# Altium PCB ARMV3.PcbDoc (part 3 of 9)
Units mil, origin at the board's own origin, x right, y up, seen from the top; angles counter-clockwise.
Board outline 4700.79 x 3937.01 mil, 6 copper layers (Top Layer, GND02, ART03, ART04, PWR05, Bottom Layer); 703 components, 513 nets, 2343 pads, 1252 vias.

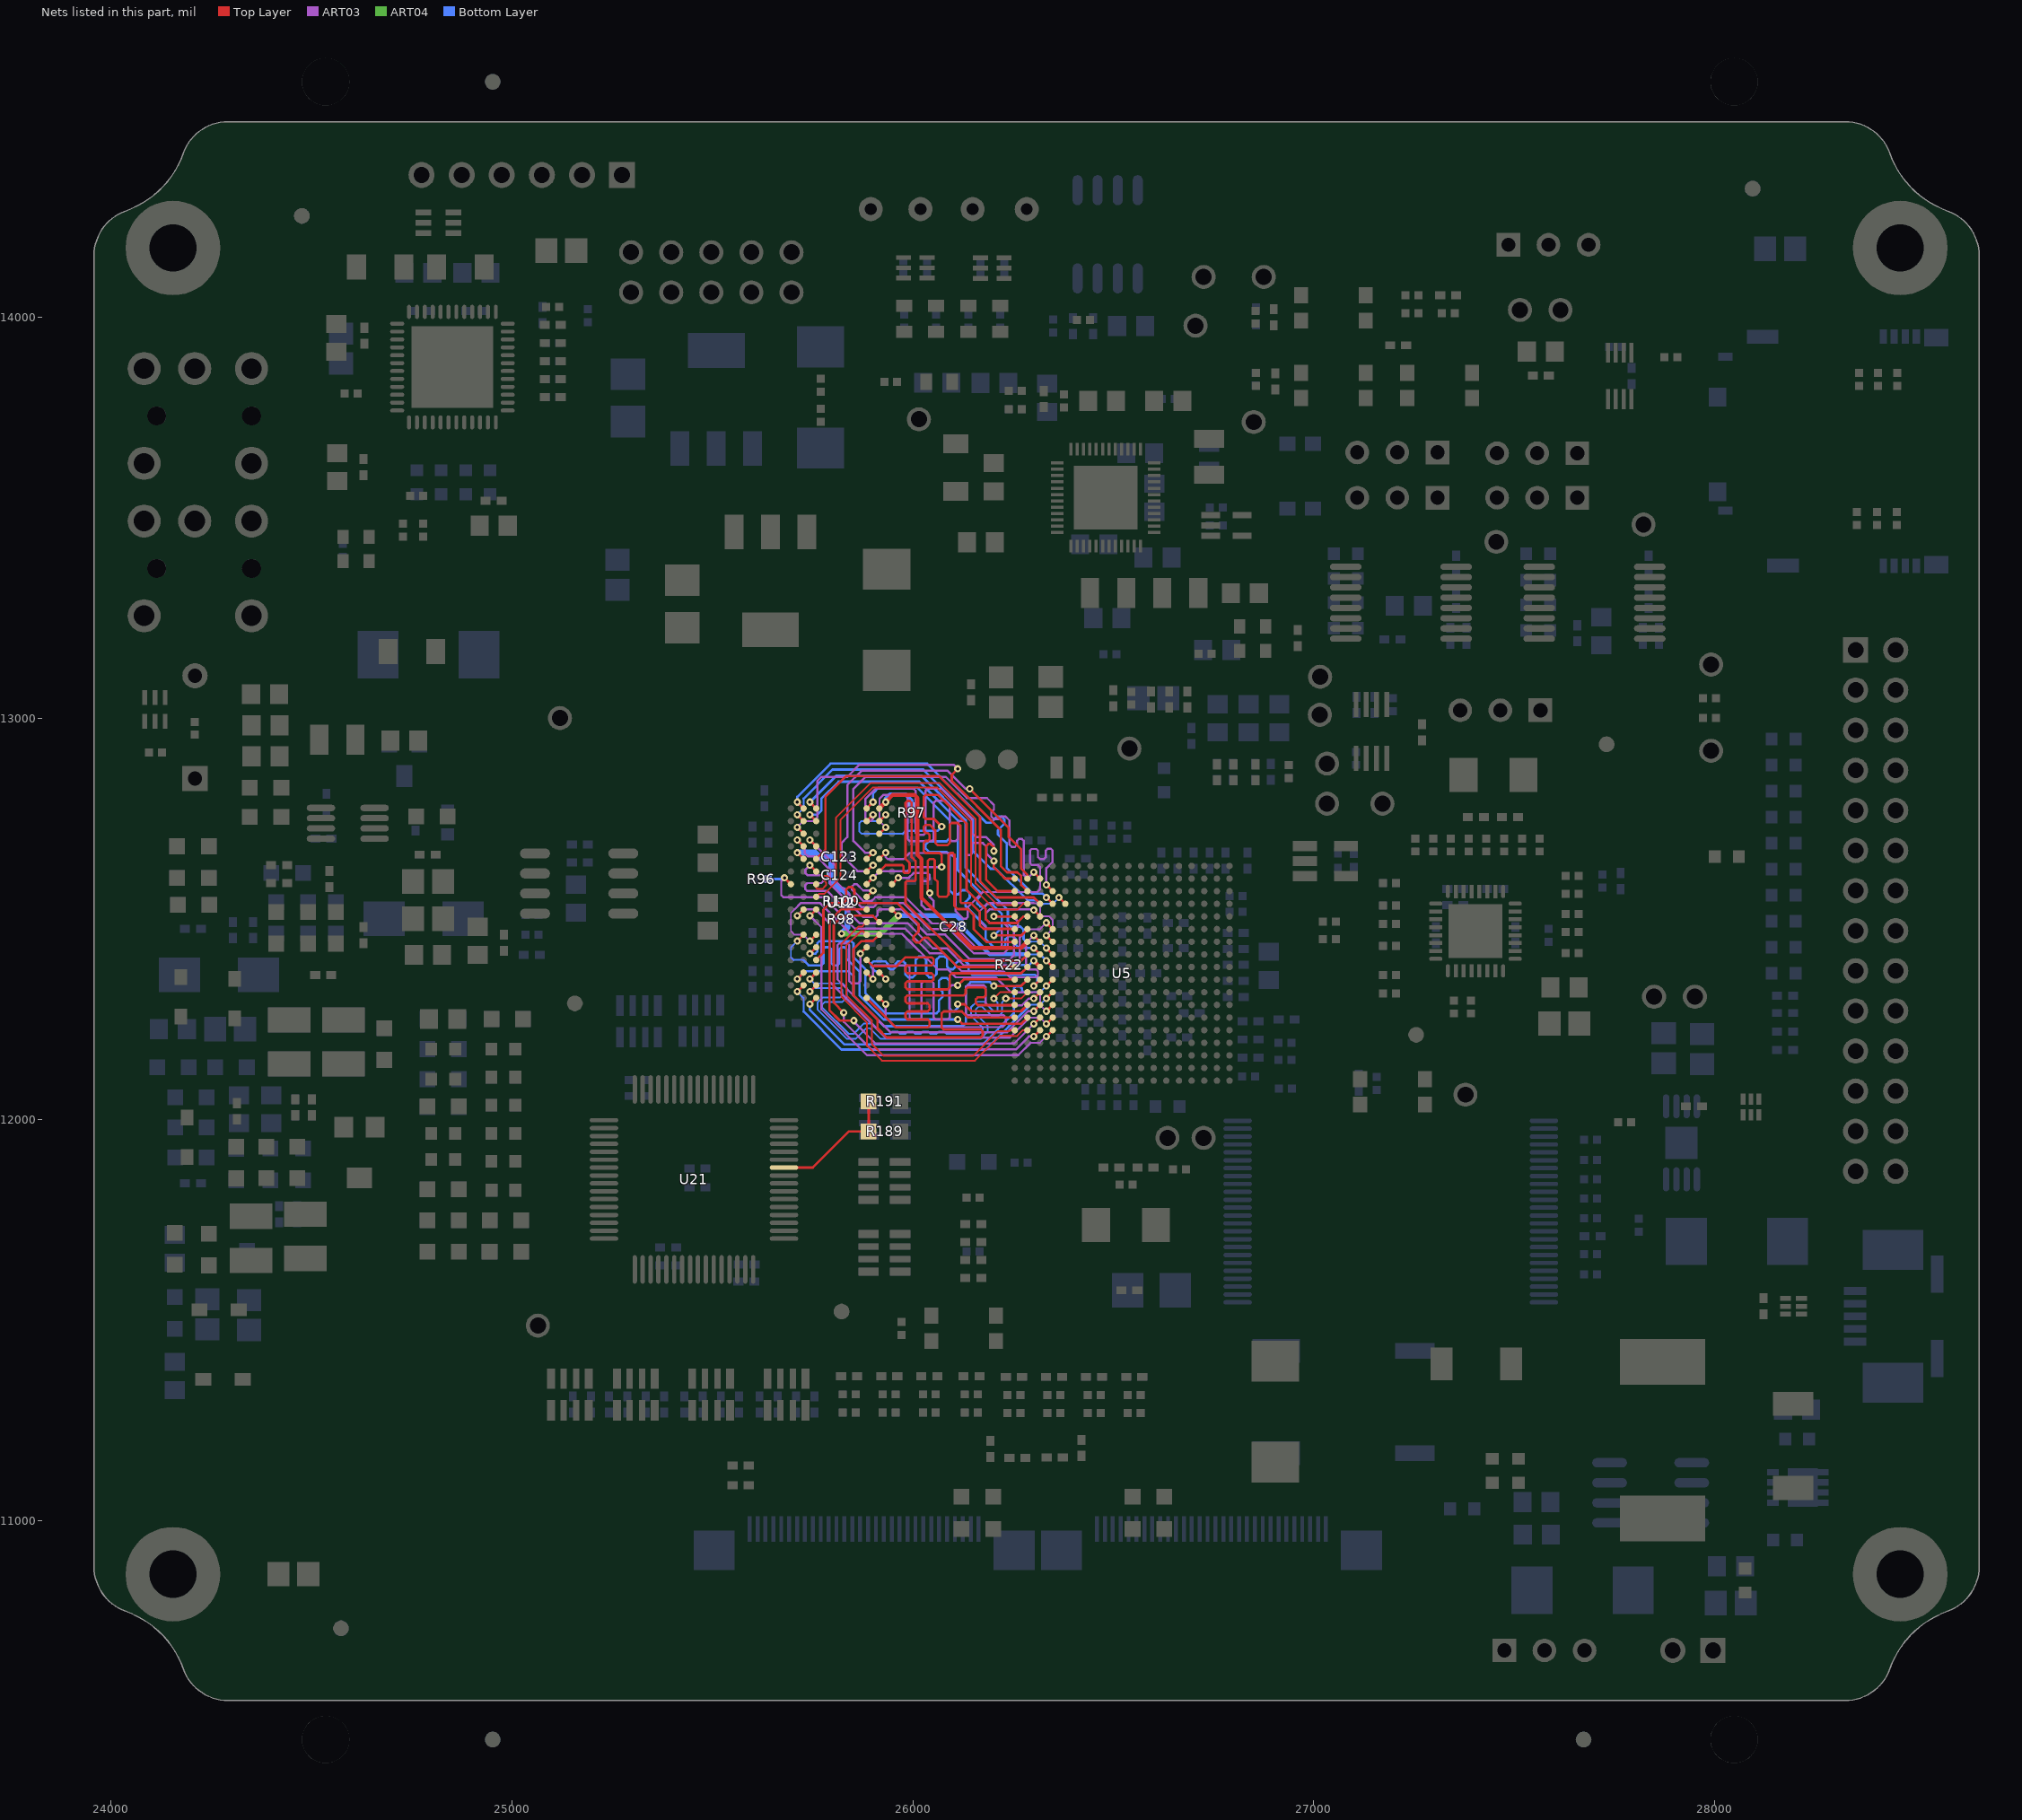
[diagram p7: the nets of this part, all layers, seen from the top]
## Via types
v1: diameter 20, hole 10, Top Layer to Bottom Layer, tented both sides, 948 vias
v2: diameter 18, hole 8, Top Layer to Bottom Layer, tented both sides, 274 vias
v3: diameter 20, hole 10, Top Layer to Bottom Layer, 18 vias
v4: diameter 22, hole 10, Top Layer to Bottom Layer, tented both sides, 7 vias
v5: diameter 22, hole 12, Top Layer to Bottom Layer, 4 vias
v6: diameter 39.37, hole 19.68, Top Layer to Bottom Layer, 1 vias

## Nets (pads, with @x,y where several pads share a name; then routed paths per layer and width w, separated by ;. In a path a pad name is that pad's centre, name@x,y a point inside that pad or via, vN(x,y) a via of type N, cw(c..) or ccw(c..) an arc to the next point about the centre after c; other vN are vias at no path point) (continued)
DDR_A4: U5.C2 U12.P8 | length 948.9
  Top Layer w6: v2(25711.77,12727.95) U12.P8@25727.51,12712.2 ; v2(26111.98,12874) 26096.98,12859 26096.98,12844 26219.39,12721.59 26219.39,12631.21 26234.6,12616 26260.58,12616 26270.13,12606.45 26270.13,12584.35 U5.C2@26285.76,12568.72
  ART03 w4.4: v2@25711.73,12728 25727.49,12743.76 25751.74,12743.76
  ART03 w5.5: 25751.74,12743.76 25761.98,12754 25761.98,12844 25771.98,12854 25836.98,12854 25866.98,12884 26101.98,12884 v2(26111.98,12874)
DDR_A5: U5.B1 U12.P2 | length 943.4
  Top Layer w6: U12.P2@25916.49,12712.2 v2(25932.23,12727.95) ; v2(26201.98,12644) 26201.98,12628.04 26218.98,12611.04 ; 26218.98,12611.02 26229.78,12600.22 U5.B1@26254.26,12600.22
  ART03 w4.4: 25916.98,12799 25916.49,12798.51 25916.49,12743.74 v2@25932.23,12728
  ART03 w5.5: 25916.98,12799 25926.98,12809 25981.98,12809 25986.98,12804 25986.98,12699 25991.98,12694 26046.98,12694 26051.98,12699 26051.98,12789 26056.98,12794 26081.98,12794 26091.98,12784 26091.98,12699 26096.98,12694 26106.98,12694 26111.98,12699 26111.98,12739 26116.98,12744 26126.98,12744 26131.98,12739 26131.98,12662 26134.98,12659 26143.98,12659 26146.98,12662 26146.98,12686 26149.98,12689 26174.73,12689 26184.48,12679.25 26184.48,12661.5 v2(26201.98,12644)
DDR_A6: U5.D5 U12.R8 | length 949.5
  Top Layer w6: v2(25711.77,12759.44) U12.R8@25727.51,12743.69 ; v2(26364.48,12553) U5.D5@26380.25,12537.23
  Bottom Layer w4.4: v2(25711.77,12759.44) 25727.49,12775.16 25727.49,12799.51 ; 26325.68,12537.5 26348.98,12537.5 v2(26364.48,12553)
  Bottom Layer w6: 25727.49,12799.51 25799.98,12872 26026,12872 26149.99,12748.01 26149.99,12669.01 26194,12625 26207,12625 26286,12546 26308,12546 26316.75,12537.25 26325.68,12537.25
DDR_A7: U5.E2 U12.R2 | length 948.2
  Top Layer w6: U12.R2@25916.49,12743.69 v2(25932.23,12759.44) ; v2(26071.98,12729.99) 26052.97,12749 26031.98,12749 26026.98,12754 26026.98,12804 26031.98,12809 26061.98,12809 26134,12736.98 26134,12571.98 26181.98,12524 26181.98,12499 26191.55,12489.43 26220,12489.43 26220.11,12489.54 26259.71,12489.54 26275.9,12505.73 U5.E2@26285.76,12505.73
  Bottom Layer w4.4: v2@25932.23,12759.5 25916.49,12743.76 25871.98,12743.76 25866.98,12738.76 25866.98,12717.26 25871.98,12712.26 25975.24,12712.26
  Bottom Layer w6: 25975.24,12712.26 25981.99,12719.01 26061,12719.01 v2(26071.98,12729.99)
DDR_A8: U5.D4 U12.T8 | length 945
  Top Layer w6: v2(25711.77,12790.94) U12.T8@25727.51,12775.19 ; v2(26332.98,12553) U5.D4@26348.75,12537.23
  Bottom Layer w6: v2@25711.73,12791 25711.73,12803.75 25794.98,12887 26035.49,12887 26183.04,12739.45 26194.07,12739.45 26209.86,12755.24 26220.89,12755.24 26228.24,12747.89 26228.24,12736.86 26212.45,12721.07 26212.45,12710.04 26234,12688.49 26234,12627 26298,12563 26322.98,12563 v2(26332.98,12553)
DDR_A9: U5.C1 U12.R3 | length 948.6
  Top Layer w6: U12.R3@25884.99,12743.69 v2(25900.73,12759.44) ; v2(26201.98,12669) 26201.98,12678.02 26193.4,12686.6 26188.4,12686.6 26182.9,12681.1 26182.9,12597.3 26211.48,12568.72 U5.C1@26254.26,12568.72
  ART03 w5.5: v2(25900.73,12759.44) 25900.73,12749 25895.73,12744 25886.98,12744 25881.98,12749 25881.98,12798.98 25907,12824 26001.98,12824 26006.98,12819 26006.98,12714 26011.98,12709 26026.98,12709 26031.98,12714 26031.98,12819 26036.98,12824 26071.98,12824 26146.98,12749 26146.98,12714 26156.98,12704 26181.98,12704 26201.98,12684 v2(26201.98,12669)
DDR_A10: U5.F4 U12.L7 | length 943
  Top Layer w6: v2(25743.27,12633.46) U12.L7@25759.01,12617.71 ; v2(26332.98,12490) U5.F4@26348.75,12474.24
  ART03 w4.4: 26287.22,12474.24 26317.22,12474.24 v2(26332.98,12490)
  ART03 w5.5: v2@25743.23,12633.5 25731.98,12622.25 25731.98,12614 25736.98,12609 25771.98,12609 25776.98,12604 25776.98,12594 25771.98,12589 25736.98,12589 25731.98,12584 25731.98,12574 25736.98,12569 25786.98,12569 25866.98,12489 25986.98,12489 26049.48,12426.5 26084.48,12426.5 26127.23,12383.75 26251.73,12383.75 26266.98,12399 26266.98,12454 26287.22,12474.24
DDR_A11: U5.F2 U12.R7 | length 945
  Top Layer w6: v2(25743.27,12759.44) U12.R7@25759.01,12743.69 ; v2(26201.98,12458.5) 26269.99,12458.47 U5.F2@26285.76,12474.24
  Bottom Layer w6: v2@25743.23,12759.5 25761.98,12759.5 25771.98,12769.5 25771.98,12799 25814.98,12842 26016,12842 26112,12746 26112,12621.98 26167.53,12566.45 26167.53,12555.42 26161.11,12549 26161.11,12537.97 26168.46,12530.62 26179.49,12530.62 26185.91,12537.04 26196.94,12537.04 26221.98,12512 26221.98,12478.5 v2(26201.98,12458.5)
DDR_A12: U5.E3 U12.N7 | length 948.2
  Top Layer w6: v2(25743.27,12696.45) U12.N7@25759.01,12680.7 ; v2(26301.48,12521.5) U5.E3@26317.26,12505.73
  ART03 w5.5: v2@25743.23,12696.5 25806.98,12632.75 25806.98,12594 25871.98,12529 25901.98,12529 25911.73,12538.75 25977.23,12538.75 26041.98,12474 26091.98,12474 26151.98,12414 26226.98,12414 26236.98,12424 26236.98,12479 26226.98,12489 26191.98,12489 26181.98,12499 26181.98,12514 26191.98,12524 26298.98,12524 v2(26301.48,12521.5)
DDR_A13: U5.H3 U12.T3 | length 945
  Top Layer w6: U12.T3@25884.99,12775.19 v2(25900.73,12790.94) ; v2(26301.48,12427) U5.H3@26317.26,12411.24
  Bottom Layer w6: v2(25900.73,12790.94) 25900.73,12812.73 25915,12827 26011,12827 26092,12746 26092,12700.8 26084.2,12693 26039.8,12693 26032,12685.2 26032,12674.8 26039.8,12667 26084.2,12667 26092,12659.2 26092,12570.98 26102.15,12560.83 26113.18,12560.83 26123.36,12571.01 26134.39,12571.01 26141.75,12563.66 26141.75,12552.63 26131.57,12542.45 26131.57,12531.41 26181.98,12481 26181.98,12449.02 26204,12427 26223.2,12427 26231,12434.8 26231,12449.14 26238.8,12456.94 26249.2,12456.94 26257,12449.14 26257,12434.8 26264.8,12427 v2(26301.48,12427)
DDR_A14: U5.H4 U12.T7 | length 943.5
  Top Layer w6: v2(25743.27,12790.94) U12.T7@25759.01,12775.19 ; v2(26332.98,12427) U5.H4@26348.75,12411.24
  Bottom Layer w4.4: 26294.18,12442.99 26316.99,12442.99 v2(26332.98,12427)
  Bottom Layer w6: v2@25743.23,12791 25809.23,12857 26021,12857 26132,12746 26132,12627 26236.98,12522.02 26236.98,12488.02 26244.5,12480.5 26268.5,12480.5 26276,12473 26276,12449 26282.25,12442.75 26294.18,12442.75
DDR_A15: U5.D3 U12.M7 | length 946.6
  Top Layer w6: U12.M7@25758.98,12649.25 25781.98,12672.25 25781.98,12803.98 25834,12856 26064.98,12856 26167.8,12753.18 26167.8,12593.6 26208.31,12553.09 26301.4,12553.09 U5.D3@26317.26,12537.23
DDR_BA0: U5.C4 U12.M2 | length 946.1
  Top Layer w6: U12.M2@25916.49,12649.21 v2(25932.23,12664.96) ; v2(26332.98,12584.5) U5.C4@26348.75,12568.72
  ART03 w4.4: 26317.24,12579.23 26317.24,12629
  ART03 w5.5: v2(25932.23,12664.96) 25932.23,12654 25937.32,12648.91 25976.89,12648.91 25991.98,12664 26091.98,12664 26106.98,12649 26106.98,12519 26125.77,12500.21 26133.19,12500.21 26136.98,12504 26136.98,12529 26174.58,12566.6 26310.33,12566.6 26317.24,12573.51 26317.24,12579.23 ; 26317.24,12629 26312.24,12634 26296.98,12634 26291.98,12639 26291.98,12670 26295.98,12674 26307.98,12674 26311.98,12670 26311.98,12654 26316.98,12649 26326.98,12649 26331.98,12654 26331.98,12670.1 26336.88,12675 26343.82,12675 26348.45,12670.37 26348.45,12641.45 26332.98,12625.98 v2(26332.98,12584.5)
DDR_BA1: U5.E1 U12.N8 | length 947.4
  Top Layer w6: v2(25711.77,12696.45) U12.N8@25727.51,12680.7 ; v2(26201.98,12505.73) U5.E1@26254.26,12505.73
  ART03 w5.5: v2@25711.73,12696.5 25730.6,12677.63 25730.6,12663.51 25738.98,12655.13 25760.85,12655.13 25793.1,12622.88 25793.1,12587.88 25876.98,12504 25906.98,12504 25911.98,12509 25911.98,12519 25916.98,12524 25971.98,12524 26035.49,12460.49 26080.49,12460.49 26141.98,12399 26241.98,12399 26251.98,12409 26251.98,12469 26261.98,12479 26261.98,12494 26250.25,12505.73 v2(26201.98,12505.73)
DDR_BA2: U5.B3 U12.M3 | length 945
  Top Layer w6: U12.M3@25884.99,12649.21 v2(25900.73,12664.96) ; v2(26301.48,12616) U5.B3@26317.26,12600.22
  ART03 w5.5: v2(25900.73,12664.96) 25881.02,12664.96 25851.98,12694 25851.98,12824 25881.98,12854 26081.98,12854 26134.99,12800.99 26185.01,12800.99 26202.34,12783.66 26202.34,12772.84 26195.58,12766.07 26195.58,12755.26 26202.79,12748.04 26213.61,12748.04 26220.37,12754.81 26231.19,12754.81 26241,12745 26241,12684.98 26246.98,12679 26254.48,12679 26259.48,12684 26259.48,12694 26264.48,12699 26271.98,12699 26276.98,12694 26276.98,12609 26281.98,12604 26289.48,12604 v2(26301.48,12616)
DDR_CASN: U5.F1 U12.K3 | length 942.1
  Top Layer w6: U12.K3@25884.99,12586.21 v2(25900.73,12601.96) ; U12.K3@25884.98,12586.25 v2(25900.73,12601.96) ; v2(26071.98,12629) 26071.98,12659 26066.98,12664 26031.98,12664 26026.98,12669 26026.98,12689 26031.98,12694 26036.98,12694 26041.98,12699 26041.98,12709 26036.98,12714 26031.98,12714 26026.98,12719 26026.98,12729 26031.98,12734 26042,12734 26056.24,12719.76 26056.24,12690 26063.04,12683.2 26086.18,12683.2 26091.98,12689 26091.98,12734 26096.98,12739 26111.98,12739 26118.78,12732.2 26118.78,12542.2 26121.98,12539 26145.4,12539 26166.98,12517.42 26166.98,12484.24 26176.42,12474.8 26253.7,12474.8 U5.F1@26254.26,12474.24
  ART03 w5.5: v2(25900.73,12601.96) 25916.99,12618.26 25986.24,12618.26 25996.98,12629 v2(26071.98,12629)
DDR_CKE: R96.2 U5.G3 U12.K9 | length 1011.5
  Top Layer w6: v2(25680.27,12601.96) U12.K9@25696.02,12586.21 ; v2(26301.51,12458.49) U5.G3@26317.26,12442.74 v2(26301.51,12458.49)
  ART03 w5.5: v2@25680.23,12602 25671.98,12593.75 25671.98,12559 25676.98,12554 25776.98,12554 25855.58,12475.4 25980.58,12475.4 26041.98,12414 26076.98,12414 26121.98,12369 26226.98,12369 26241.98,12354 26306.98,12354 26311.98,12359 26311.98,12369 26306.98,12374 26286.98,12374 26281.98,12379 26281.98,12439 v2(26301.51,12458.49)
  Bottom Layer w6: R96.2@25642,12598.97 25677.29,12598.97 v2(25680.27,12601.96)
DDR_CLK: U5.D2 U12.J7 | length 949.8
  Top Layer w4.4: U12.J7@25759.01,12554.72 25766.39,12562.1 25779.1,12562.1 25819.9,12602.9 25819.9,12747.07 25899.83,12827 26061,12827 26145,12743 26145,12583.17 26205.65,12522.52 26260.06,12522.52 26274.77,12537.23 U5.D2@26285.76,12537.23
DDR_CLKN: U5.D1 U12.K7 | length 948
  Top Layer w4.4: U12.K7@25759.01,12586.21 25759.01,12576.99 25762,12574 25774.17,12574 25783.61,12583.44 25783.61,12590.57 25776.95,12597.24 25776.95,12604.36 25780,12607.42 25787.13,12607.42 25793.8,12600.75 25800.92,12600.75 25808,12607.83 25808,12752 25894.9,12838.9 26065.93,12838.9 26156.9,12747.93 26156.9,12588.1 26210.58,12534.42 26251.45,12534.42 U5.D1@26254.26,12537.23
DDR_CSN: U5.H2 U12.L2 | length 962.5
  Top Layer w6: U12.L2@25916.49,12617.71 25932.23,12633.46 ; U12.L2@25916.48,12617.75 25932.35,12633.62 25973.98,12633.62 25976.98,12630.62 25976.98,12617 25979.98,12614 25988.98,12614 25991.98,12617 25991.98,12639 25981.98,12649 25981.98,12789 25986.98,12794 25992.23,12794 25997.23,12789 25997.23,12654 26006.98,12644.25 26006.98,12597 26003.98,12594 25984.98,12594 25981.98,12591 25981.98,12539 26125.5,12395.48 26270,12395.48 U5.H2@26285.76,12411.24
DDR_D0: U5.M3 U12.E3 | length 919.7
  Top Layer w6: v2(25869.24,12412.99) U12.E3@25884.99,12428.73 ; v2(26301.48,12269.5) U5.M3@26317.26,12285.26
  ART03 w5.5: v2(25869.24,12412.99) 25869.23,12344 25864.23,12339 25846.98,12339 25841.98,12344 25841.98,12434 25836.98,12439 25816.98,12439 25811.98,12434 25811.98,12349 25943.58,12217.4 26235.38,12217.4 26287.48,12269.5 v2(26301.48,12269.5)
DDR_D1: U5.M4 U12.F7 | length 920.4
  Top Layer w6: v2(25743.27,12444.49) U12.F7@25759.01,12460.23 ; v2(26332.98,12269.5) U5.M4@26348.75,12285.26
  ART03 w4.4: 25705.11,12523.49 25695.99,12514.37 25695.99,12469.48 25705.23,12460.24 25727.49,12460.24 v2@25743.23,12444.5 ; 26298.34,12316.76 26310.91,12316.76 26317.22,12310.45 26317.22,12285.26 v2(26332.98,12269.5)
  ART03 w5.5: 25705.11,12523.49 25720.37,12538.75 25768.95,12538.75 25845.1,12462.6 25973.38,12462.6 26061.98,12374 26086.98,12374 26106.98,12354 26206.98,12354 26244.22,12316.76 26298.34,12316.76
DDR_D2: U5.N1 U12.F2 | length 917.4
  Top Layer w6: U12.F2@25916.48,12460.25 25900.71,12444.48 25881.98,12444.48 25881.88,12444.38 25872.38,12444.38 25852.23,12424.23 25852.23,12308.75 25911.98,12249 25911.98,12227 25934.98,12204 26169.38,12204 26174.38,12209 26174.38,12219 26169.38,12224 26076.98,12224 26071.98,12229 26071.98,12264 26076.98,12269 26121.98,12269 26137.22,12253.76 U5.N1@26254.26,12253.76
DDR_D3: U5.N2 U12.F8 | length 918.6
  Top Layer w6: v2(25711.77,12444.49) U12.F8@25727.51,12460.23 ; v2(26111.98,12249) 26122.52,12238.46 26270.46,12238.46 U5.N2@26285.76,12253.76
  Bottom Layer w4.4: v2(25711.77,12444.49) 25696,12428.72 25696,12404 25703,12397 25703.26,12397.26 25726.98,12397.26
  Bottom Layer w6: 25726.98,12397.26 25740.24,12384 25771.98,12384 25776.98,12389 25776.98,12424 25781.98,12429 25791.98,12429 25796.98,12424 25796.98,12389 25801.98,12384 25811.98,12384 25816.98,12389 25816.98,12424 25821.98,12429 25829.48,12429 25834.48,12424 25834.48,12401.5 25866.98,12369 25866.98,12309 25926.98,12249 v2(26111.98,12249)
DDR_D4: U5.N3 U12.H3 | length 915.4
  Top Layer w6: v2(25853,12246) 25818,12246 25791.98,12272.02 25791.98,12494 25821.23,12523.25 U12.H3@25884.98,12523.25 ; v2(26301.48,12238) U5.N3@26317.26,12253.76
  ART03 w5.5: v2(25853,12246) 25853,12242.98 25906.98,12189 26252.48,12189 v2(26301.48,12238)
DDR_D5: U5.N4 U12.H8 | length 917.3
  Top Layer w6: v2(25711.77,12507.48) U12.H8@25727.51,12523.22 ; v2(26332.98,12238) U5.N4@26348.75,12253.76
  ART03 w4.4: 26291.74,12253.76 26317.22,12253.76 v2(26332.98,12238)
  ART03 w5.5: v2@25711.73,12507.5 25728.23,12524 25756.98,12524 25791.98,12489 25791.98,12344 25931.98,12204 26241.98,12204 26291.74,12253.76
DDR_D6: U5.P3 U12.G2 | length 919.6
  Top Layer w6: v2(25828,12266) 25803,12291 25803,12485.02 25825.6,12507.62 25900.6,12507.62 U12.G2@25916.49,12491.73 ; v2(26301.48,12206.5) U5.P3@26317.26,12222.27
  ART03 w5.5: v2(25828,12266) 25828,12242.98 25896.98,12174 26256.98,12174 26289.48,12206.5 v2(26301.48,12206.5)
DDR_D7: U5.P4 U12.H7 | length 917.5
  Top Layer w6: v2(25743.27,12507.48) U12.H7@25759.01,12523.22 ; v2(26332.98,12206.5) U5.P4@26348.75,12222.27
  ART03 w4.4: 26293.72,12190.74 26317.22,12190.74 v2(26332.98,12206.5)
  ART03 w5.5: v2@25743.23,12507.5 25771.98,12478.75 25771.98,12274 25885.99,12159.99 26262.97,12159.99 26293.72,12190.74
DDR_D8: U5.J1 U12.D7 | length 799
  Top Layer w6: U12.D7@25758.98,12397.25 25776.98,12415.25 25776.98,12522.98 25793,12539 25827.2,12539 25833.5,12545.3 25833.5,12572.7 25839.8,12579 25848.2,12579 25854.5,12572.7 25854.5,12545.3 25860.8,12539 25961.98,12539 26014.18,12486.8 26014.18,12467.91 26002.02,12455.74 26002.02,12446.83 26007.96,12440.89 26016.87,12440.89 26029.03,12453.06 26037.94,12453.06 26111.25,12379.75 U5.J1@26254.26,12379.75
DDR_D9: U5.K1 U12.C3 | length 799.8
  Top Layer w6: U12.C3@25884.98,12365.75 v2(25900.73,12350) ; v2(26111.98,12334) 26126.8,12348.82 26253.69,12348.82 U5.K1@26254.26,12348.25
  ART03 w5.5: v2(25900.73,12350) 25900.73,12379 25905.73,12384 25986.98,12384 25991.98,12379 25991.98,12254 25996.98,12249 26016.98,12249 26021.98,12254 26021.98,12339 26026.98,12344 26046.98,12344 26051.98,12339 26051.98,12254 26056.98,12249 26086.98,12249 26091.98,12254 26091.98,12329 26096.98,12334 v2(26111.98,12334)
DDR_D10: U5.K2 U12.C8 | length 798.3
  Top Layer w6: v2(25711.77,12350) U12.C8@25727.51,12365.74 ; v2(26201.98,12332.52) 26270.03,12332.52 U5.K2@26285.76,12348.25
  Bottom Layer w6: v2@25711.73,12350 25730.73,12369 25840,12369 25851.98,12357.02 25851.98,12308.02 25928,12232 26124,12232 26132.49,12240.49 26132.49,12330.49 26144,12342 26192.5,12342 v2(26201.98,12332.52)
DDR_D11: U5.K3 U12.C2 | length 795.8
  Top Layer w6: U12.C2@25916.49,12365.74 v2(25932.23,12350) ; v2(26301.48,12332.5) U5.K3@26317.26,12348.25
  Bottom Layer w6: v2(25932.23,12350) 25913.23,12369 25907,12369 25897,12379 25897,12389 25902,12394 25931.45,12394 25937.38,12388.08 25937.38,12379.93 25943.3,12374 25951.2,12374 25957.12,12379.93 25957.12,12388.08 25963.05,12394 25976,12394 25981.2,12388.8 25981.2,12361.8 25989,12354 25999.4,12354 26007.2,12361.8 26007.2,12398.2 26015,12406 26025.4,12406 26033.2,12398.2 26033.2,12361.8 26041,12354 26051.4,12354 26059.2,12361.8 26059.2,12398.2 26067,12406 26079.2,12406 26085.5,12399.7 26085.5,12380.3 26091.8,12374 26100.2,12374 26106.5,12380.3 26106.5,12387.7 26114.8,12396 26130,12396 26139,12387 26139,12370 26149,12360 26305,12360 26310.99,12354.01 26310.99,12342.01 v2(26301.48,12332.5)
DDR_D12: U5.K4 U12.A7 | length 796.4
  Top Layer w6: v2(25743.27,12287.01) U12.A7@25759.01,12302.75 ; v2(26332.98,12332.5) U5.K4@26348.75,12348.25
  Bottom Layer w4.4: 26276.98,12316.74 26317.22,12316.74 v2(26332.98,12332.5)
  Bottom Layer w6: v2@25743.23,12287 25743.23,12272.75 25829.48,12186.5 26174.48,12186.5 26251.98,12264 26251.98,12326.5 26256.98,12331.5 26266.98,12331.5 26271.98,12326.5 26271.98,12321.74 26276.98,12316.74
DDR_D13: U5.L3 U12.A2 | length 798.8
  Top Layer w6: U12.A2@25916.49,12302.75 v2(25932.23,12287.01) ; v2(26301.48,12301) U5.L3@26317.26,12316.76
  ART03 w5.5: v2(25932.23,12287.01) 25932.23,12253.75 25956.18,12229.8 26223.77,12229.8 26231.98,12238.01 26231.98,12254 26226.98,12259 26136.98,12259 26131.98,12264 26131.98,12329 26136.98,12334 26176.98,12334 26181.98,12329 26181.98,12289 26186.98,12284 26271.98,12284 26288.98,12301 v2(26301.48,12301)
DDR_D14: U5.L4 U12.B8 | length 798.6
  Top Layer w6: v2(25711.77,12318.51) U12.B8@25727.51,12334.25 ; v2(26332.98,12301) U5.L4@26348.75,12316.76
  Bottom Layer w4.4: v2(25711.77,12318.51) 25727.77,12302.51 25727.77,12268.77 25727.49,12268.49 ; 26293.22,12285.24 26317.22,12285.24 v2(26332.98,12301)
  Bottom Layer w6: 25727.49,12268.49 25821.98,12174 26181.98,12174 26293.22,12285.24
DDR_D15: U5.M1 U12.A3 | length 793
  Top Layer w6: U12.A3@25884.99,12302.75 25958.73,12229 26036.98,12229 26041.98,12234 26041.98,12244 26036.98,12249 25986.98,12249 25981.98,12254 25981.98,12264 25986.98,12269 26036.98,12269 26041.98,12274 26041.98,12284 26036.98,12289 25986.98,12289 25981.98,12294 25981.98,12304 25986.98,12309 26126.98,12309 26131.98,12314 26131.98,12324 26136.98,12329 26176.98,12329 26181.98,12324 26181.98,12309 26176.98,12304 26161.98,12304 26156.98,12299 26156.98,12290.25 26162.53,12284.7 26253.7,12284.7 U5.M1@26254.26,12285.26
DDR_DQM0: U5.M2 U12.E7 | length 909.3
  Top Layer w6: v2(25743.27,12412.99) U12.E7@25759.01,12428.73 ; v2(26111.98,12287) 26128.98,12287 26146.49,12269.49 26269.99,12269.49 U5.M2@26285.76,12285.26
  Bottom Layer w6: v2@25743.23,12413 25756.98,12413 25761.98,12418 25761.98,12439 25766.98,12444 25846.98,12444 25851.98,12439 25851.98,12404 25881.98,12374 25881.98,12314 25931.98,12264 26059,12264 26065,12270 26065,12296 26074,12305 26074,12318 26065,12327 26065,12345 26072,12352 26085,12352 26091,12346 26091,12277 26099,12269 26103,12269 26112,12278 v2(26111.98,12287)
DDR_DQM1: U5.J2 U12.D3 | length 793.8
  Top Layer w6: U12.D3@25884.98,12397.25 25900.71,12381.52 25959.5,12381.52 25981.98,12404 26046.98,12404 26051.98,12399 26051.98,12389 26046.98,12384 25986.98,12384 25981.98,12379 25981.98,12369 25986.98,12364 26046.98,12364 26051.98,12359 26051.98,12349 26046.98,12344 25986.98,12344 25981.98,12339 25981.98,12329 25986.98,12324 26086.98,12324 26091.98,12329 26091.98,12359 26096.98,12364 26270.01,12364 U5.J2@26285.76,12379.75
DDR_DQS0: U5.P1 U12.F3 | length 736.3
  Top Layer w4.4: U12.F3@25884.99,12460.23 25876.22,12469 25870,12469 25834,12433 25834,12309.83 25898,12245.83 25898,12188 25928,12158 26150.17,12158 26212.17,12220 26241.73,12220 26244,12222.27 U5.P1@26254.26,12222.27
DDR_DQS1: U5.L1 U12.C7 | length 941.2
  Top Layer w4.4: v2(26201.98,12301) 26217.75,12316.76 U5.L1@26254.26,12316.76
  Top Layer w6: v2(25743.27,12350) U12.C7@25759.01,12365.74
  Bottom Layer w4.4: v2(25743.27,12350) 25754.36,12338.9 25824.93,12338.9 25835.9,12327.93 25835.9,12304.07 25823.93,12292.1 25780.1,12292.1 25774,12286 25774,12279 25840,12213 25853,12213 25878.9,12238.9 25898.1,12238.9 25924,12213 25943,12213 25949,12219 25962,12219 25968,12213 25981,12213 25987,12219 26000,12219 26006,12213 26019,12213 26025,12219 26038,12219 26044,12213 26059,12213 26065,12219 26078,12219 26084,12213 26165,12213 26174.59,12222.59 26174.59,12228.59 26145.1,12258.07 26145.1,12279.03 26159.07,12293 26178,12293 26202,12269 26209.03,12269 26211.03,12271 26211.03,12291.95 v2(26201.98,12301)
DDR_DQSN0: U5.P2 U12.G3 | length 813.3
  Top Layer w4.4: U12.G3@25884.99,12491.73 25874.15,12480.9 25865.07,12480.9 25822.1,12437.93 25822.1,12304.9 25886.1,12240.9 25886.1,12183.07 25923.07,12146.1 26155.1,12146.1 26217.1,12208.1 26247.93,12208.1 26248.25,12207.77 26260.27,12207.77 26274.77,12222.27 U5.P2@26285.76,12222.27
DDR_DQSN1: U5.L2 U12.B7 | length 941.5
  Top Layer w4.4: v2(26231.98,12301) 26269.99,12300.99 U5.L2@26285.76,12316.76
  Top Layer w6: v2(25743.27,12318.51) U12.B7@25759.01,12334.25
  Bottom Layer w4.4: v2(25743.27,12318.51) 25751.76,12327 25820,12327 25824,12323 25824,12309 25819,12304 25775.17,12304 25762.1,12290.93 25762.1,12274.07 25835.07,12201.1 25857.93,12201.1 25883.83,12227 25893,12227 25918.9,12201.1 26169.93,12201.1 26186.49,12217.66 26186.49,12233.51 26157,12263 26157,12274.1 26164,12281.1 26173.07,12281.1 26197.07,12257.1 26213.96,12257.1 26222.93,12266.07 26222.93,12291.95 v2(26231.98,12301)
DDR_ODT: U5.G1 U12.K1 | length 949.6
  Top Layer w6: U12.K1@25947.98,12586.21 v2(25963.73,12601.96) ; v2(26041.98,12564) 26036.98,12569 26036.98,12644 26041.98,12649 26051.24,12649 26054.64,12645.6 26054.64,12599.2 26061.98,12591.86 26061.98,12559 26066.24,12554.74 26083.46,12554.74 26089.52,12560.8 26089.52,12659.82 26093.7,12664 26099.6,12664 26103.78,12659.82 26103.78,12532.2 26111.98,12524 26136.98,12524 26151.98,12509 26151.98,12474 26183.78,12442.2 26253.72,12442.2 U5.G1@26254.26,12442.74
  ART03 w5.5: v2(25963.73,12601.96) 25989.98,12602 26001.98,12614 26036.98,12614 26041.98,12609 26041.98,12599 26036.98,12594 26026.98,12594 26021.98,12589 26021.98,12534 26031.98,12524 26046.98,12524 26051.98,12529 26051.98,12544 26041.98,12554 v2(26041.98,12564)
DDR_RASN: U5.G4 U12.J3 | length 943.8
  Top Layer w6: U12.J3@25884.99,12554.72 v2(25900.73,12570.47) ; v2(26333,12458.49) U5.G4@26348.75,12442.74
  ART03 w4.4: 26300.98,12539 26307.22,12539 26317.22,12529 26317.22,12513.76 26325.24,12505.74 26340.24,12505.74 26348.72,12497.26 26348.72,12474.24 v2(26333,12458.49)
  ART03 w5.5: v2(25900.73,12570.47) 25876.23,12570.5 25860.89,12585.85 25853.83,12585.85 25848.02,12580.04 25848.02,12572.96 25876.98,12544 25896.98,12544 25906.48,12553.5 25982.48,12553.5 26047.73,12488.25 26097.73,12488.25 26156.98,12429 26216.98,12429 26221.98,12434 26221.98,12469.49 26215.47,12476 26184.98,12476 26166.98,12494 26166.98,12519 26186.98,12539 26300.98,12539
DDR_RESETN: R97.2 U5.G2 U12.T2 | length 786.9
  Top Layer w6: 26245.52,12426.97 26269.99,12426.97
  Top Layer w10: U12.T2@25916.49,12775.19 v2(25932.23,12790.94) ; v2@25932.23,12791 25950.47,12809.24 26003.76,12809.24 26011.98,12801.02 26011.98,12659 26021.98,12649 26021.98,12552.02 26147.03,12426.97 26245.52,12426.97 ; 26270.01,12427 U5.G2@26285.76,12442.74
  Bottom Layer w10: v2(25932.23,12790.94) 25932.23,12799.23 25943,12810 25982,12810 25997.23,12794.77 R97.2@25997.23,12780.14
DDR_VREF: C28.1 C123.1 C124.1 R98.2 R100.1 U5.J4 U12.H1 U12.M8 | length 961.7
  Top Layer w6: v2(25711.77,12664.96) U12.M8@25727.51,12649.21 ; U12.H1@25947.98,12523.22 v2(25963.73,12507.48) ; v2(26333,12395.5) U5.J4@26348.75,12379.75
  ART04 w15: v2(25822,12463) 25919.25,12463 v2(25963.73,12507.48)
  Bottom Layer w4.4: 26287,12411.24 26317.24,12411.24
  Bottom Layer w6: 26317.24,12411.24 v2(26333,12395.5)
  Bottom Layer w10: C28.1@26121,12480 26123,12480 26191.76,12411.24 26287,12411.24
  Bottom Layer w12: v2@25963.73,12507.79 v2(25963.73,12507.48) 26109.52,12507.48 26121,12496 C28.1@26121,12480
  Bottom Layer w15: v2(25711.77,12664.96) 25756.19,12664.96 25756.23,12665 25767.26,12653.97 C123.1@25797,12653.97 25797,12591 25815,12573 25825,12573 25837,12561 R98.2@25837,12498.97 25837,12478 v2(25822,12463)
DDR_VTP: R22.2 U5.J3 | length 94.3
  Top Layer w6: v2(26301.51,12395.5) U5.J3@26317.26,12379.75
  Top Layer w10: v2(26301.51,12395.5) U5.J3@26317.26,12379.75
  Bottom Layer w6: R22.2@26256.14,12385 26291.02,12385 v2(26301.51,12395.5)
DDR_WEN: U5.B2 U12.L3 | length 926.3
  Top Layer w6: U12.L3@25884.99,12617.71 v2(25900.73,12633.46) ; v2(26141.98,12824) 26238.99,12726.99 26238.99,12704.01 26270.13,12672.87 26270.13,12625.25 26285.76,12609.62 U5.B2@26285.76,12600.22
  ART03 w5.5: v2(25900.73,12633.46) 25886.23,12619 25861.98,12619 25821.98,12659 25821.98,12689 25836.98,12704 25836.98,12834 25871.98,12869 26086.98,12869 26131.73,12824.25 26141.73,12824.25 v2(26141.98,12824)
DENBH: R189.1 R191.1 U21.42 | length 323.7
  Top Layer w6: U21.42@25678.78,11879.53 25750.53,11879.53 25841,11970 R189.1@25890,11970 R191.1@25890,12045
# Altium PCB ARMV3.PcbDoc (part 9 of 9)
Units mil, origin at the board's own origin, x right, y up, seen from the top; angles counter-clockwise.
Board outline 4700.79 x 3937.01 mil, 6 copper layers (Top Layer, GND02, ART03, ART04, PWR05, Bottom Layer); 703 components, 513 nets, 2343 pads, 1252 vias.

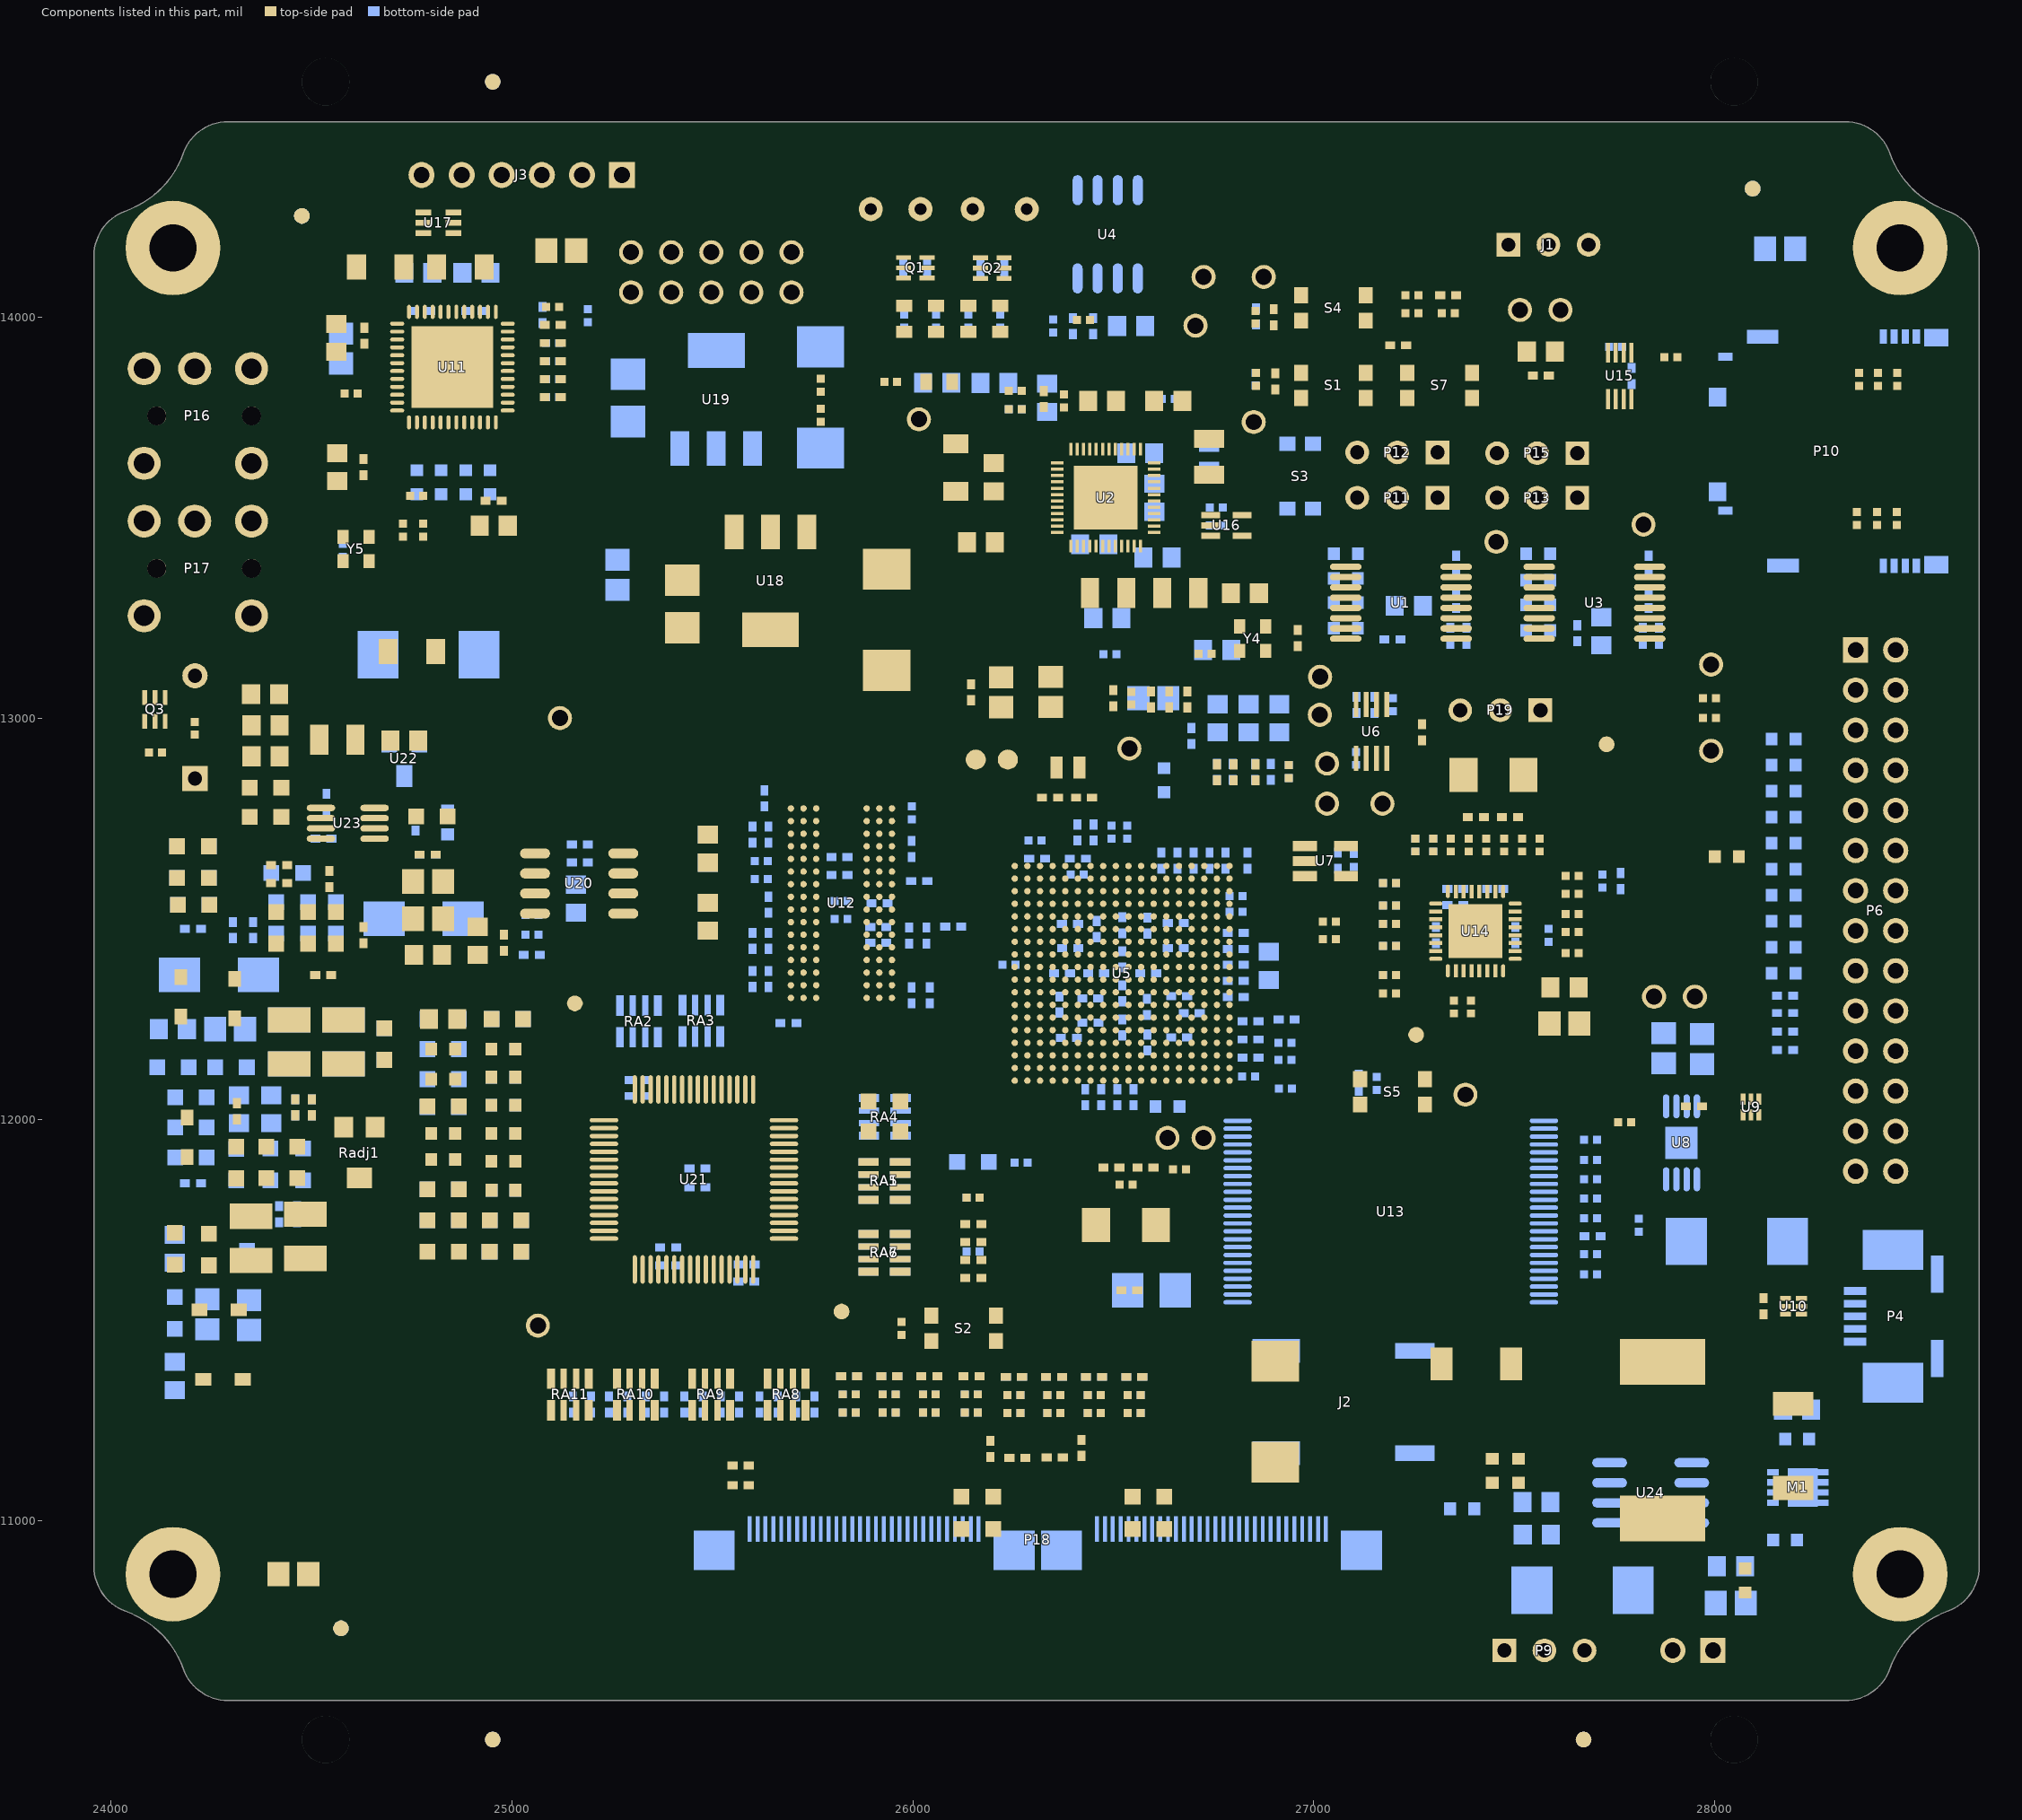
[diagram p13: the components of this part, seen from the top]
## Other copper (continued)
Bottom Layer:
  rectangle net VDD_5V0: 25200,13374.57 25330,13417.57
  rectangle net VDD_5V0: 25239.12,13394.87 25288.12,13440
  rectangle net VDD_5V: 25216.7,13297.47 25312.2,13340.47
  region net VDD_5V: 25235.2,13326.47 25235.2,13278.47 25285.2,13278.47 25285.2,13326.47
  region net DGND: 24960.12,13242.57 24875.12,13242.57 24875.12,13081.57 24960.12,13081.57
  region net DGND: 24999.12,13206.57 24842.12,13206.57 24842.12,13114.57 24999.12,13114.57
  region net VDD_5V0: 24706.12,13250.57 24624.12,13250.57 24624.12,13070.57 24706.12,13070.57
  region net VDD_5V0: 24758.12,13205.57 24590.12,13205.57 24590.12,13109.57 24758.12,13109.57
  rectangle net USB1_PWR: 27853.12,12092.57 27893.12,12130.57
  rectangle net USB1_PWR: 27949.12,12077.57 27986.12,12127.57
  rectangle net USB1_PWR: 27811.12,12116.57 27980.12,12158.57
  rectangle net DGND: 28151.12,11615.57 28216.12,11774.57
  rectangle net DGND: 28107.12,11666.57 28251.12,11727.57
  rectangle net SYS_5V: 27953.12,11666.57 28006.12,11723.57
  rectangle net SYS_5V: 27897.12,11605.57 27961.12,11775.57
  rectangle net GND_EARTH: 28502.12,11366.57 28566.12,11649.57
  rectangle net GND_EARTH: 28532.43,13339 28574.43,13429
  rectangle net GND_EARTH: 28528.43,13904 28572.43,13986.21
  rectangle net GND_EARTH: 28064.43,13940 28179.43,13964
  rectangle net GND_EARTH: 28092.43,13914 28145.43,13984
  rectangle net GND_EARTH: 27991.43,13762.23 28022.43,13839.23
  rectangle net GND_EARTH: 27969.43,13784 28049.43,13818
  rectangle net GND_EARTH: 28139.43,13344 28199.43,13419
  rectangle net NetC147_1: 27919.12,10951.57 27969.12,10993.57
  rectangle net NetC147_1: 27958.12,10867.57 28011.12,10901.57
  rectangle net NetC147_1: 27989.12,10740.57 28020.12,10930.57
  rectangle net NetC147_1: 27940.12,10770.57 28010.12,10814.57
  rectangle net VDD_5V0: 28077.4,10772.57 28136.12,10802.57
  rectangle net NetC147_1: 27767.12,10743.57 27830.12,10904.57
  rectangle net NetC147_1: 27717.12,10793.61 27859.29,10852.57
  rectangle net DGND: 27514.12,10746.57 27576.12,10844.57
  rectangle net DGND: 27449.12,10782.57 27629.12,10850.57
  region net VDD_3V3C: 24628.4,13866.45 24628.4,13902.45 24528.4,13902.45 24528.4,13866.45
  region net VDD_3V3C: 24592.4,13836.45 24592.4,13870.45 24555.4,13870.45 24555.4,13836.45
  rectangle net VDD_1V8B: 25730,13595 25810,13745
  rectangle net VDD_1V8B: 25690,13635 25850,13710
  rectangle net VDD_1V8B: 25495,13610 25525,13735
  rectangle net VDD_1V8B: 25520,13645 25550,13700
  rectangle net VDD_5V0: 25402.66,13610.34 25434.66,13740.34
  rectangle net VDD_5V0: 25365,13646 25443.07,13699
  rectangle net GND_EARTH: 28092.43,13677.79 28145.43,13747.79
  rectangle net GND_EARTH: 27991.43,13552.26 28022.43,13603.02
  rectangle net GND_EARTH: 27959.43,13547.79 28049.43,13581.79
  rectangle net VDD_5V0: 25228.69,13715 25357,13745
  rectangle net VDD_5V0: 25262,13680 25317,13715
  rectangle net NetC241_1: 24643,12929 24780,12960
  rectangle net DGND: 26407,13246 26464,13266
  rectangle net DGND: 26440,13205 26462,13261
  rectangle net VDDS_DDR: 26505,13201 26536,13272
  rectangle net VDDS_DDR: 26505,13244 26567,13272
  rectangle net DGND: 25364,12831 25430,12859
  rectangle net DGND: 25365,12792 25390,12888
  rectangle net DGND: 25431,12695 25546,12725
  rectangle net DGND: 25474,12710 25505,12755
  rectangle net VDDS_DDR: 25433,12629 25540,12655
  rectangle net VDDS_DDR: 25476,12540 25501,12640
  rectangle net VDDS_DDR: 25437,12530 25542,12555
  region net 3V3_AUD: 24591.4,13980.45 24591.4,14006.45 24556.4,14006.45 24556.4,13980.45
  region net 3V3_AUD: 24619.62,13950.45 24619.62,13973.45 24528.62,13973.45 24528.62,13950.45
  rectangle net DGND: 25731.12,13854 25808.12,14001.57
  rectangle net DGND: 25688.12,13887.8 25870,13960.6
  rectangle net NetD6_1: 28261.49,11120.24 28283.19,11150.59
  rectangle net NetD6_1: 28261.49,11012.4 28280.91,11043.48
  region net DGND: 25538,12452 25538,12483 25442,12483 25442,12452
  region net DGND: 25501,12419 25501,12486 25476,12486 25476,12419
  rectangle net DGND: 26860,11110 26950,11210
  rectangle net DGND: 26820,11150 26990,11190
  rectangle net NetC149_1: 26860,11360 26950,11480
  rectangle net NetC149_1: 26830,11400 26980,11445
  text "BOTTOM" at 26890,14811 h100
GND02 (plane layer: these items are gaps in the copper):
  lines w40: 23957.93,11107.57 24314.12,11107.57 24393.12,11028.57 24393.12,10678.57 24439.12,10632.57 28238.12,10632.57 28279.12,10673.57 28279.12,10926.57 28411.12,11058.57 28411.12,11756.57 28508.12,11853.57 28508.12,13898.57 28438.12,13968.57 28294.12,13968.57 28251.12,14011.57 28251.12,14314.57 28165.12,14400.57 24433.12,14400.57 24375.12,14342.57 24375.12,14020.57 24324.12,13969.57 23984.93,13969.57 23957.98,13942.63 23957.98,13871.98 23957.98,11069.79 ; 23960.98,13169.57 24405.12,13169.57 24447.12,13211.57 24447.12,13708.59 24468.11,13729.57 25099.12,13729.57 25124.12,13754.57 25124.12,14400.57
  text "GND02" at 24288,14802 h100
PWR05 (plane layer: these items are gaps in the copper):
  circle w80: c24351,13373.62 r12
  circle w80: c24114.78,13373.62 r12
  circle w80: c24351,13753.89 r12
  circle w80: c24114.78,13753.89 r12
  pour cut-out: 23975.92,10845.92 cw(c23983,10853) 23972.99,10853 23972.99,11087.56 23957.93,11087.56 cw(c23957.93,11107.57) 23957.93,11127.59 24314.12,11127.59 cw(c24314.12,11107.57) 24328.31,11121.69 24328.28,11121.73 24407.28,11042.73 24407.24,11042.76 cw(c24393.12,11028.57) 24413.14,11028.57 24413.14,10686.86 24448.42,10651.59 28228.83,10651.59 28259.11,10681.86 28259.11,10926.57 cw(c28279.12,10926.57) 28265.01,10940.76 28264.97,10940.73 28391.11,11066.86 28391.11,11756.57 cw(c28411.12,11756.57) 28397.01,11770.76 28396.97,11770.73 28488.11,11861.86 28488.11,13890.28 28429.83,13948.56 28307.12,13948.56 cw(c28307.12,13968.57) 28292.94,13954.46 28292.97,13954.42 28236.97,14010.42 28237.01,14010.39 cw(c28251.12,14024.57) 28231.11,14024.57 28231.11,14306.28 28156.83,14380.56 24441.42,14380.56 24395.14,14334.28 24395.14,14020.57 cw(c24375.12,14020.57) 24389.24,14006.39 24389.28,14006.42 24338.28,13955.42 24338.31,13955.46 cw(c24324.12,13969.57) 24324.12,13949.56 23973.12,13949.56 cw(c23973.12,13969.57) 23967.99,13988.92 23967.99,14176 cw(c23978,14176) 23970.92,14183.08 24260.92,14473.08 cw(c24268,14466) 24268,14476.01 28347,14476.01 cw(c28347,14466) 28354.08,14473.08 28649.08,14178.08 cw(c28642,14171) 28652.01,14171 28652.01,10872 cw(c28642,10872) 28649.08,10864.92 28337.08,10552.92 cw(c28330,10560) 28330,10549.99 24276,10549.99 cw(c24276,10560) 24268.92,10552.92
  lines w15: 24447.12,13325.89 25138.05,13325.89 25200.89,13388.73 25200.89,13540.28 25243.4,13582.79 25583.48,13582.79 25639,13527.27 25639,13000.66 ; 25254.12,12737.57 24685.12,12737.57 24655,12707.45 24655,11855 24726,11784 24816,11694 24816,11033.8 24844.8,11005 27082.45,11005 27112.06,11034.61 27112.06,12598.77 27112.06,12624.58 27242.12,12754.64 27242.12,14005.34 ; 25738,11005 25738,12059.88 ; 25898.75,14406.7 25898.75,13800.19 26028.48,13670.46 26028.48,13309.31 ; 26378.4,12225 26623.55,12225 26632.12,12233.57 26632.12,12473.57 26632.12,12534.65 26632.12,12658.57 26958.12,12984.57 26958.12,13647.57 26940.12,13665.57 26677.7,13665.57 ; 26677.7,13320.72 26677.7,13736.17 26655.29,13758.57 26352.12,13758.57 26324.12,13786.57 26324.12,13978.46 26351.01,14005.34 27140.24,14005.34 27241.94,14005.34 27241.94,14030.33 27280.99,14069.39 27816.29,14069.39 27863.06,14022.61 27863.06,11567.57 27112.06,11567.57 ; 26678.17,13318.57 26029.5,13318.57 26028.48,13317.55 26028.48,13078.48 25948.88,12998.88 25511.43,12998.88 25338.12,12825.57 25254.12,12741.57 25254.12,12089.57 25283.82,12059.88 26349.43,12059.88 26378.4,12088.85 26378.4,12352.76 26378.4,12871.85 26678.17,13171.62 26678.17,13320.25 ; 27840.12,11567.57 28410.12,11567.57 ; 28656.85,13041.85 28656.85,13185
  lines w20: 23978,13969.57 23978,14176 24268,14466 28347,14466 28642,14171 28642,10872 28330,10560 24276,10560 23983,10853 23983,11107.57
  lines w40: 23957.93,11107.57 24314.12,11107.57 24393.12,11028.57 24393.12,10678.57 24440.12,10631.57 28237.12,10631.57 28279.12,10673.57 28279.12,10926.57 28411.12,11058.57 28411.12,11756.57 28508.12,11853.57 28508.12,13898.57 28438.12,13968.57 28307.12,13968.57 28251.12,14024.57 28251.12,14314.57 28165.12,14400.57 24433.12,14400.57 24375.12,14342.57 24375.12,14020.57 24324.12,13969.57 23973.12,13969.57 ; 23960.98,13169.57 24400.12,13169.57 24447.12,13216.57 24447.12,13708.59 24468.11,13729.57 25099.12,13729.57 25124.12,13754.57 25124.12,14400.57
  text "PWR05" at 25812,14809 h100

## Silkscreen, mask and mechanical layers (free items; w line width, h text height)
Top Overlay:
  circle w5: c26352,11966 r32.61
  lines w5: 24122,11892 24122,11747.87 24269,11747.87 24269,11821.13 24281.5,11821.13 ; 24236,12138.64 24236,11970.34 24530,11970.34 24530,12081.09 24378.17,12081.09 ; 24451,12870 24466,12870 24471,12865 24471,12848 24482,12837 24606,12837 ; 27328,12648.17 27328,12635 27882,12635 27882,12710 ; 27529.3,12761 27531.3,12759 27578,12759 27593,12774 27649,12774 27650,12775 27650,12897 ; 25630,11033 26084,11033 26084,11134 26104,11134 26118,11134 26118,11176 26118,11237 26194,11237 26194,11406 25780,11406 25780,11195 25732,11195 25630,11195 25630,11033 ; 26205,11232 26720,11232 26720,11543 26681,11543 26245,11543 26245,11396 26205,11396 26205,11367.09 26205,11232 ; 26865,12135 27030,12135 27030,12275 27245,12275 27245,12620 27140,12620 27140,12410 26865,12410 26865,12135
  text "ZFCS" at 25356.66,12939.69 h100
  text "eMMC_RSTn" at 26260,12014 h25
Bottom Overlay:
  lines w4: 26825,12810 26860.81,12810 26860.81,12716.08 26992.99,12716.08 26992.99,12920 26825,12920 26825,12810
  lines w5: 24134.13,12570.5 24021,12570.5 24021,12733 24276.22,12733 24276.22,12712.24 ; 24381.32,12573.24 24525,12573.24 24525,12664 24576,12664 24576,12714 24714,12714 24714,12699 24714,12577 24592.5,12577 24592.5,12568 ; 25585,12504 25622,12504 ; 26321.06,11884 26365,11884 26365,11935 26321.06,11935 ; 26630,12540 26630,12590 26690,12590 26690,12540 ; 26208.06,11635.61 26336.11,11635.61 26395.06,11635.61 26689.24,11635.61 26689.24,11826.61 26593.06,11826.61 26593.06,11999.61 26321.06,11999.61 26321.06,11855.61 26208.06,11855.61 26208.06,11635.61 ; 26315,12170 26480,12170 26480,12130 26630,12130 26630,12180.61 26750,12180.61 26750,12350 26710,12350 26710,12540 26490,12540 26490,12400 26330,12400 26315,12400 26315,12170
  text "A" at 26670,12550 h30
  text "A" at 26348,11896 h30
Mechanical 1:
  lines w10: 24292.34,10550.61 cw(c24292.34,10668.72) 24180.99,10629.35 ccw(c23958.27,10550.61) 24037.01,10773.32 cw(c24076.39,10884.68) 23958.27,10884.68 23958.27,14153.56 cw(c24076.38,14153.56) 24037.01,14264.91 ccw(c23958.27,14487.62) 24180.99,14408.88 cw(c24292.34,14369.51) 24292.34,14487.62 ; 24292.34,10550.61 23958,10550.61 23958,10432.5 ccw(c24036.74,10432.5) 24036.74,10353.76 28580.32,10353.76 ccw(c28580.32,10432.5) 28659.06,10432.5 28659.06,10550.61 28325,10550.61 ; 24292.34,10550.61 28325,10550.61 ; 24292.34,14487.62 28325,14487.62 ; 24292.34,14487.62 23958.28,14487.62 23958.28,14605.73 cw(c24037.02,14605.73) 24037.02,14684.47 28580.6,14684.47 cw(c28580.6,14605.73) 28659.34,14605.73 28659.34,14487.62 28325,14487.62 ; 28325,10550.61 ccw(c28325,10668.72) 28436.35,10629.35 cw(c28659.06,10550.62) 28580.32,10773.32 ccw(c28540.95,10884.68) 28659.06,10884.68 28659.06,14153.56 ccw(c28540.95,14153.56) 28580.32,14264.91 cw(c28659.06,14487.62) 28436.35,14408.88 ccw(c28325,14369.52) 28325,14487.62
Mechanical 5:
  circle w5: c28462.21,14172.66 r59.06
  circle w5: c24155.12,14172.66 r59.06
  circle w5: c24155.12,10865.57 r59.06
  circle w5: c28462.21,10865.57 r59.06

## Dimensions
23958,10550.61 to 24292.34,14487.62 on Drill Drawing
23958.27,10884.68 to 28659.06,10884.68 on Drill Drawing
